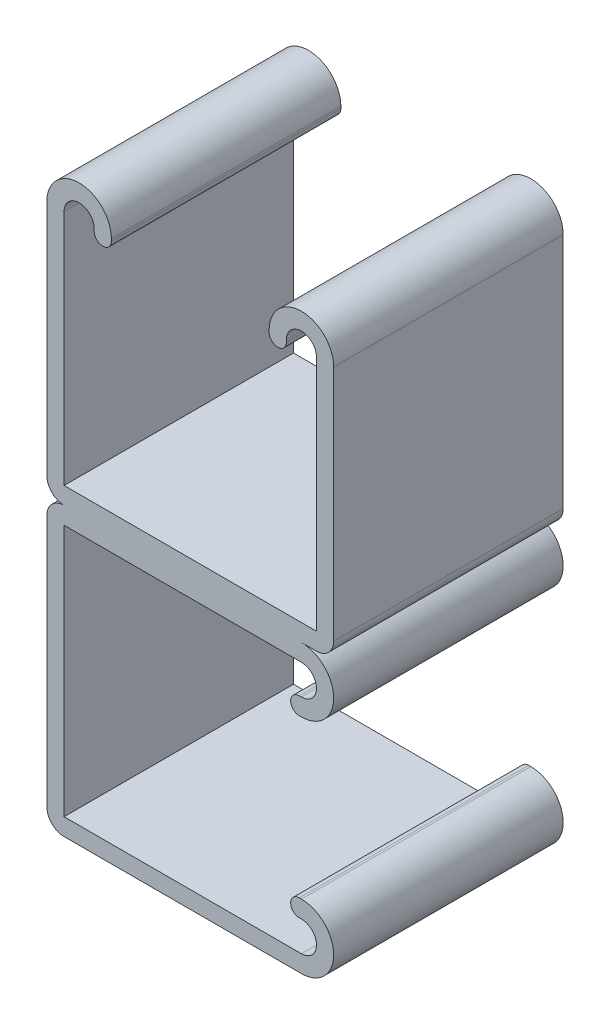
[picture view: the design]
ISO-10303-21;
HEADER;
FILE_DESCRIPTION(('STEP AP214'),'2;1');
FILE_NAME('part.step','',(''),(''),'','','');
FILE_SCHEMA(('AUTOMOTIVE_DESIGN { 1 0 10303 214 1 1 1 1 }'));
ENDSEC;
DATA;
#1=APPLICATION_CONTEXT('core data for automotive mechanical design processes');
#2=APPLICATION_PROTOCOL_DEFINITION('international standard','automotive_design',2000,#1);
#3=PRODUCT_CONTEXT('',#1,'mechanical');
#4=PRODUCT('Part','Part','',(#3));
#5=PRODUCT_RELATED_PRODUCT_CATEGORY('part','',(#4));
#6=PRODUCT_DEFINITION_FORMATION('','',#4);
#7=PRODUCT_DEFINITION_CONTEXT('part definition',#1,'design');
#8=PRODUCT_DEFINITION('design','',#6,#7);
#9=PRODUCT_DEFINITION_SHAPE('','',#8);
#10=(LENGTH_UNIT() NAMED_UNIT(*) SI_UNIT(.MILLI.,.METRE.));
#11=(NAMED_UNIT(*) PLANE_ANGLE_UNIT() SI_UNIT($,.RADIAN.));
#12=(NAMED_UNIT(*) SI_UNIT($,.STERADIAN.) SOLID_ANGLE_UNIT());
#13=UNCERTAINTY_MEASURE_WITH_UNIT(LENGTH_MEASURE(1.E-05),#10,'distance_accuracy_value','');
#14=(GEOMETRIC_REPRESENTATION_CONTEXT(3) GLOBAL_UNCERTAINTY_ASSIGNED_CONTEXT((#13)) GLOBAL_UNIT_ASSIGNED_CONTEXT((#10,
#11,#12)) REPRESENTATION_CONTEXT('',''));
#15=CARTESIAN_POINT('',(0.,0.,0.));
#16=DIRECTION('',(0.,0.,1.));
#17=DIRECTION('',(1.,0.,0.));
#18=AXIS2_PLACEMENT_3D('',#15,#16,#17);
#19=CARTESIAN_POINT('',(1.905,0.,12.7));
#20=DIRECTION('',(0.,1.,0.));
#21=DIRECTION('',(0.,0.,1.));
#22=AXIS2_PLACEMENT_3D('',#19,#20,#21);
#23=PLANE('',#22);
#24=DIRECTION('',(0.,0.,-1.));
#25=VECTOR('',#24,1.);
#26=CARTESIAN_POINT('',(28.178125,2.93849150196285E-13,12.7));
#27=LINE('',#26,#25);
#28=CARTESIAN_POINT('',(28.178125,0.,12.7));
#29=VERTEX_POINT('',#28);
#30=CARTESIAN_POINT('',(28.178125,2.93849150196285E-13,-12.7));
#31=VERTEX_POINT('',#30);
#32=EDGE_CURVE('E205',#29,#31,#27,.T.);
#33=ORIENTED_EDGE('',*,*,#32,.T.);
#34=DIRECTION('',(1.,0.,0.));
#35=VECTOR('',#34,1.);
#36=CARTESIAN_POINT('',(1.905,0.,-12.7));
#37=LINE('',#36,#35);
#38=CARTESIAN_POINT('',(29.845,0.,-12.7));
#39=VERTEX_POINT('',#38);
#40=EDGE_CURVE('E209',#31,#39,#37,.T.);
#41=ORIENTED_EDGE('',*,*,#40,.T.);
#42=DIRECTION('',(0.,0.,-1.));
#43=VECTOR('',#42,1.);
#44=CARTESIAN_POINT('',(29.845,0.,12.7));
#45=LINE('',#44,#43);
#46=CARTESIAN_POINT('',(29.845,0.,12.7));
#47=VERTEX_POINT('',#46);
#48=EDGE_CURVE('E271',#47,#39,#45,.T.);
#49=ORIENTED_EDGE('',*,*,#48,.F.);
#50=DIRECTION('',(1.,0.,0.));
#51=VECTOR('',#50,1.);
#52=CARTESIAN_POINT('',(1.905,0.,12.7));
#53=LINE('',#52,#51);
#54=EDGE_CURVE('E48',#29,#47,#53,.T.);
#55=ORIENTED_EDGE('',*,*,#54,.F.);
#56=EDGE_LOOP('',(#33,#41,#49,#55));
#57=FACE_BOUND('',#56,.T.);
#58=ADVANCED_FACE('F33',(#57),#23,.F.);
#59=CARTESIAN_POINT('',(3.571875,28.178125,12.7));
#60=DIRECTION('',(0.,0.,-1.));
#61=DIRECTION('',(-1.,0.,0.));
#62=AXIS2_PLACEMENT_3D('',#59,#60,#61);
#63=CYLINDRICAL_SURFACE('',#62,3.571875);
#64=CARTESIAN_POINT('',(3.571875,28.178125,-12.7));
#65=DIRECTION('',(0.,0.,1.));
#66=DIRECTION('',(-1.,0.,0.));
#67=AXIS2_PLACEMENT_3D('',#64,#65,#66);
#68=CIRCLE('',#67,3.571875);
#69=CARTESIAN_POINT('',(7.14375,28.178125,-12.7));
#70=VERTEX_POINT('',#69);
#71=CARTESIAN_POINT('',(0.,28.178125,-12.7));
#72=VERTEX_POINT('',#71);
#73=EDGE_CURVE('E201',#70,#72,#68,.T.);
#74=ORIENTED_EDGE('',*,*,#73,.T.);
#75=DIRECTION('',(0.,0.,-1.));
#76=VECTOR('',#75,1.);
#77=CARTESIAN_POINT('',(0.,28.178125,12.7));
#78=LINE('',#77,#76);
#79=CARTESIAN_POINT('',(0.,28.178125,12.7));
#80=VERTEX_POINT('',#79);
#81=EDGE_CURVE('E11',#80,#72,#78,.T.);
#82=ORIENTED_EDGE('',*,*,#81,.F.);
#83=CARTESIAN_POINT('',(3.571875,28.178125,12.7));
#84=DIRECTION('',(0.,0.,1.));
#85=DIRECTION('',(-1.,0.,0.));
#86=AXIS2_PLACEMENT_3D('',#83,#84,#85);
#87=CIRCLE('',#86,3.571875);
#88=CARTESIAN_POINT('',(7.14375,28.178125,12.7));
#89=VERTEX_POINT('',#88);
#90=EDGE_CURVE('E237',#89,#80,#87,.T.);
#91=ORIENTED_EDGE('',*,*,#90,.F.);
#92=DIRECTION('',(0.,0.,-1.));
#93=VECTOR('',#92,1.);
#94=CARTESIAN_POINT('',(7.14375,28.178125,12.7));
#95=LINE('',#94,#93);
#96=EDGE_CURVE('E197',#89,#70,#95,.T.);
#97=ORIENTED_EDGE('',*,*,#96,.T.);
#98=EDGE_LOOP('',(#74,#82,#91,#97));
#99=FACE_BOUND('',#98,.T.);
#100=ADVANCED_FACE('F35',(#99),#63,.T.);
#101=CARTESIAN_POINT('',(0.,28.178125,12.7));
#102=DIRECTION('',(1.,0.,0.));
#103=DIRECTION('',(0.,1.,0.));
#104=AXIS2_PLACEMENT_3D('',#101,#102,#103);
#105=PLANE('',#104);
#106=DIRECTION('',(0.,-1.,0.));
#107=VECTOR('',#106,1.);
#108=CARTESIAN_POINT('',(0.,28.178125,-12.7));
#109=LINE('',#108,#107);
#110=CARTESIAN_POINT('',(0.,1.905,-12.7));
#111=VERTEX_POINT('',#110);
#112=EDGE_CURVE('E204',#72,#111,#109,.T.);
#113=ORIENTED_EDGE('',*,*,#112,.T.);
#114=DIRECTION('',(0.,0.,-1.));
#115=VECTOR('',#114,1.);
#116=CARTESIAN_POINT('',(0.,1.905,12.7));
#117=LINE('',#116,#115);
#118=CARTESIAN_POINT('',(0.,1.905,12.7));
#119=VERTEX_POINT('',#118);
#120=EDGE_CURVE('E41',#119,#111,#117,.T.);
#121=ORIENTED_EDGE('',*,*,#120,.F.);
#122=DIRECTION('',(0.,-1.,0.));
#123=VECTOR('',#122,1.);
#124=CARTESIAN_POINT('',(0.,28.178125,12.7));
#125=LINE('',#124,#123);
#126=EDGE_CURVE('E128',#80,#119,#125,.T.);
#127=ORIENTED_EDGE('',*,*,#126,.F.);
#128=ORIENTED_EDGE('',*,*,#81,.T.);
#129=EDGE_LOOP('',(#113,#121,#127,#128));
#130=FACE_BOUND('',#129,.T.);
#131=ADVANCED_FACE('F636',(#130),#105,.F.);
#132=CARTESIAN_POINT('',(1.905,1.905,12.7));
#133=DIRECTION('',(0.,0.,-1.));
#134=DIRECTION('',(-1.,0.,0.));
#135=AXIS2_PLACEMENT_3D('',#132,#133,#134);
#136=CYLINDRICAL_SURFACE('',#135,1.905);
#137=CARTESIAN_POINT('',(1.905,1.905,-12.7));
#138=DIRECTION('',(0.,0.,1.));
#139=DIRECTION('',(-1.,0.,0.));
#140=AXIS2_PLACEMENT_3D('',#137,#138,#139);
#141=CIRCLE('',#140,1.905);
#142=CARTESIAN_POINT('',(1.905,0.,-12.7));
#143=VERTEX_POINT('',#142);
#144=EDGE_CURVE('E207',#111,#143,#141,.T.);
#145=ORIENTED_EDGE('',*,*,#144,.T.);
#146=DIRECTION('',(0.,0.,-1.));
#147=VECTOR('',#146,1.);
#148=CARTESIAN_POINT('',(1.905,0.,12.7));
#149=LINE('',#148,#147);
#150=CARTESIAN_POINT('',(1.905,0.,12.7));
#151=VERTEX_POINT('',#150);
#152=EDGE_CURVE('E274',#151,#143,#149,.T.);
#153=ORIENTED_EDGE('',*,*,#152,.F.);
#154=CARTESIAN_POINT('',(1.905,1.905,12.7));
#155=DIRECTION('',(0.,0.,1.));
#156=DIRECTION('',(-1.,0.,0.));
#157=AXIS2_PLACEMENT_3D('',#154,#155,#156);
#158=CIRCLE('',#157,1.905);
#159=EDGE_CURVE('E282',#119,#151,#158,.T.);
#160=ORIENTED_EDGE('',*,*,#159,.F.);
#161=ORIENTED_EDGE('',*,*,#120,.T.);
#162=EDGE_LOOP('',(#145,#153,#160,#161));
#163=FACE_BOUND('',#162,.T.);
#164=ADVANCED_FACE('F280',(#163),#136,.T.);
#165=CARTESIAN_POINT('',(29.845,1.905,12.7));
#166=DIRECTION('',(0.,0.,-1.));
#167=DIRECTION('',(-1.,0.,0.));
#168=AXIS2_PLACEMENT_3D('',#165,#166,#167);
#169=CYLINDRICAL_SURFACE('',#168,1.905);
#170=CARTESIAN_POINT('',(29.845,1.905,-12.7));
#171=DIRECTION('',(0.,0.,1.));
#172=DIRECTION('',(1.,0.,0.));
#173=AXIS2_PLACEMENT_3D('',#170,#171,#172);
#174=CIRCLE('',#173,1.905);
#175=CARTESIAN_POINT('',(31.75,1.905,-12.7));
#176=VERTEX_POINT('',#175);
#177=EDGE_CURVE('E211',#39,#176,#174,.T.);
#178=ORIENTED_EDGE('',*,*,#177,.T.);
#179=DIRECTION('',(0.,0.,-1.));
#180=VECTOR('',#179,1.);
#181=CARTESIAN_POINT('',(31.75,1.905,12.7));
#182=LINE('',#181,#180);
#183=CARTESIAN_POINT('',(31.75,1.905,12.7));
#184=VERTEX_POINT('',#183);
#185=EDGE_CURVE('E268',#184,#176,#182,.T.);
#186=ORIENTED_EDGE('',*,*,#185,.F.);
#187=CARTESIAN_POINT('',(29.845,1.905,12.7));
#188=DIRECTION('',(0.,0.,1.));
#189=DIRECTION('',(1.,0.,0.));
#190=AXIS2_PLACEMENT_3D('',#187,#188,#189);
#191=CIRCLE('',#190,1.905);
#192=EDGE_CURVE('E400',#47,#184,#191,.T.);
#193=ORIENTED_EDGE('',*,*,#192,.F.);
#194=ORIENTED_EDGE('',*,*,#48,.T.);
#195=EDGE_LOOP('',(#178,#186,#193,#194));
#196=FACE_BOUND('',#195,.T.);
#197=ADVANCED_FACE('F639',(#196),#169,.T.);
#198=CARTESIAN_POINT('',(31.75,1.905,12.7));
#199=DIRECTION('',(-1.,0.,0.));
#200=DIRECTION('',(0.,-1.,0.));
#201=AXIS2_PLACEMENT_3D('',#198,#199,#200);
#202=PLANE('',#201);
#203=DIRECTION('',(0.,1.,0.));
#204=VECTOR('',#203,1.);
#205=CARTESIAN_POINT('',(31.75,1.905,-12.7));
#206=LINE('',#205,#204);
#207=CARTESIAN_POINT('',(31.75,28.178125,-12.7));
#208=VERTEX_POINT('',#207);
#209=EDGE_CURVE('E213',#176,#208,#206,.T.);
#210=ORIENTED_EDGE('',*,*,#209,.T.);
#211=DIRECTION('',(0.,0.,-1.));
#212=VECTOR('',#211,1.);
#213=CARTESIAN_POINT('',(31.75,28.178125,12.7));
#214=LINE('',#213,#212);
#215=CARTESIAN_POINT('',(31.75,28.178125,12.7));
#216=VERTEX_POINT('',#215);
#217=EDGE_CURVE('E265',#216,#208,#214,.T.);
#218=ORIENTED_EDGE('',*,*,#217,.F.);
#219=DIRECTION('',(0.,1.,0.));
#220=VECTOR('',#219,1.);
#221=CARTESIAN_POINT('',(31.75,1.905,12.7));
#222=LINE('',#221,#220);
#223=EDGE_CURVE('E402',#184,#216,#222,.T.);
#224=ORIENTED_EDGE('',*,*,#223,.F.);
#225=ORIENTED_EDGE('',*,*,#185,.T.);
#226=EDGE_LOOP('',(#210,#218,#224,#225));
#227=FACE_BOUND('',#226,.T.);
#228=ADVANCED_FACE('F658',(#227),#202,.F.);
#229=CARTESIAN_POINT('',(28.178125,28.178125,12.7));
#230=DIRECTION('',(0.,0.,-1.));
#231=DIRECTION('',(-1.,0.,0.));
#232=AXIS2_PLACEMENT_3D('',#229,#230,#231);
#233=CYLINDRICAL_SURFACE('',#232,3.571875);
#234=CARTESIAN_POINT('',(28.178125,28.178125,-12.7));
#235=DIRECTION('',(0.,0.,1.));
#236=DIRECTION('',(1.,0.,0.));
#237=AXIS2_PLACEMENT_3D('',#234,#235,#236);
#238=CIRCLE('',#237,3.571875);
#239=CARTESIAN_POINT('',(24.60625,28.178125,-12.7));
#240=VERTEX_POINT('',#239);
#241=EDGE_CURVE('E215',#208,#240,#238,.T.);
#242=ORIENTED_EDGE('',*,*,#241,.T.);
#243=DIRECTION('',(0.,0.,-1.));
#244=VECTOR('',#243,1.);
#245=CARTESIAN_POINT('',(24.60625,28.178125,12.7));
#246=LINE('',#245,#244);
#247=CARTESIAN_POINT('',(24.60625,28.178125,12.7));
#248=VERTEX_POINT('',#247);
#249=EDGE_CURVE('E262',#248,#240,#246,.T.);
#250=ORIENTED_EDGE('',*,*,#249,.F.);
#251=CARTESIAN_POINT('',(28.178125,28.178125,12.7));
#252=DIRECTION('',(0.,0.,1.));
#253=DIRECTION('',(1.,0.,0.));
#254=AXIS2_PLACEMENT_3D('',#251,#252,#253);
#255=CIRCLE('',#254,3.571875);
#256=EDGE_CURVE('E404',#216,#248,#255,.T.);
#257=ORIENTED_EDGE('',*,*,#256,.F.);
#258=ORIENTED_EDGE('',*,*,#217,.T.);
#259=EDGE_LOOP('',(#242,#250,#257,#258));
#260=FACE_BOUND('',#259,.T.);
#261=ADVANCED_FACE('F665',(#260),#233,.T.);
#262=CARTESIAN_POINT('',(24.60625,28.178125,12.7));
#263=DIRECTION('',(1.,0.,0.));
#264=DIRECTION('',(0.,1.,0.));
#265=AXIS2_PLACEMENT_3D('',#262,#263,#264);
#266=PLANE('',#265);
#267=DIRECTION('',(0.,-1.,0.));
#268=VECTOR('',#267,1.);
#269=CARTESIAN_POINT('',(24.60625,28.178125,-12.7));
#270=LINE('',#269,#268);
#271=CARTESIAN_POINT('',(24.60625,27.94,-12.7));
#272=VERTEX_POINT('',#271);
#273=EDGE_CURVE('E217',#240,#272,#270,.T.);
#274=ORIENTED_EDGE('',*,*,#273,.T.);
#275=DIRECTION('',(0.,0.,-1.));
#276=VECTOR('',#275,1.);
#277=CARTESIAN_POINT('',(24.60625,27.94,12.7));
#278=LINE('',#277,#276);
#279=CARTESIAN_POINT('',(24.60625,27.94,12.7));
#280=VERTEX_POINT('',#279);
#281=EDGE_CURVE('E259',#280,#272,#278,.T.);
#282=ORIENTED_EDGE('',*,*,#281,.F.);
#283=DIRECTION('',(0.,-1.,0.));
#284=VECTOR('',#283,1.);
#285=CARTESIAN_POINT('',(24.60625,28.178125,12.7));
#286=LINE('',#285,#284);
#287=EDGE_CURVE('E406',#248,#280,#286,.T.);
#288=ORIENTED_EDGE('',*,*,#287,.F.);
#289=ORIENTED_EDGE('',*,*,#249,.T.);
#290=EDGE_LOOP('',(#274,#282,#288,#289));
#291=FACE_BOUND('',#290,.T.);
#292=ADVANCED_FACE('F672',(#291),#266,.F.);
#293=CARTESIAN_POINT('',(25.55875,27.94,12.7));
#294=DIRECTION('',(0.,0.,-1.));
#295=DIRECTION('',(-1.,0.,0.));
#296=AXIS2_PLACEMENT_3D('',#293,#294,#295);
#297=CYLINDRICAL_SURFACE('',#296,0.952500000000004);
#298=CARTESIAN_POINT('',(25.55875,27.94,-12.7));
#299=DIRECTION('',(0.,0.,1.));
#300=DIRECTION('',(1.,0.,0.));
#301=AXIS2_PLACEMENT_3D('',#298,#299,#300);
#302=CIRCLE('',#301,0.952500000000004);
#303=CARTESIAN_POINT('',(26.51125,27.94,-12.7));
#304=VERTEX_POINT('',#303);
#305=EDGE_CURVE('E219',#272,#304,#302,.T.);
#306=ORIENTED_EDGE('',*,*,#305,.T.);
#307=DIRECTION('',(0.,0.,-1.));
#308=VECTOR('',#307,1.);
#309=CARTESIAN_POINT('',(26.51125,27.94,12.7));
#310=LINE('',#309,#308);
#311=CARTESIAN_POINT('',(26.51125,27.94,12.7));
#312=VERTEX_POINT('',#311);
#313=EDGE_CURVE('E256',#312,#304,#310,.T.);
#314=ORIENTED_EDGE('',*,*,#313,.F.);
#315=CARTESIAN_POINT('',(25.55875,27.94,12.7));
#316=DIRECTION('',(0.,0.,1.));
#317=DIRECTION('',(1.,0.,0.));
#318=AXIS2_PLACEMENT_3D('',#315,#316,#317);
#319=CIRCLE('',#318,0.952500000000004);
#320=EDGE_CURVE('E408',#280,#312,#319,.T.);
#321=ORIENTED_EDGE('',*,*,#320,.F.);
#322=ORIENTED_EDGE('',*,*,#281,.T.);
#323=EDGE_LOOP('',(#306,#314,#321,#322));
#324=FACE_BOUND('',#323,.T.);
#325=ADVANCED_FACE('F680',(#324),#297,.T.);
#326=CARTESIAN_POINT('',(26.51125,28.178125,12.7));
#327=DIRECTION('',(-1.,0.,0.));
#328=DIRECTION('',(0.,-1.,0.));
#329=AXIS2_PLACEMENT_3D('',#326,#327,#328);
#330=PLANE('',#329);
#331=DIRECTION('',(0.,1.,0.));
#332=VECTOR('',#331,1.);
#333=CARTESIAN_POINT('',(26.51125,28.178125,-12.7));
#334=LINE('',#333,#332);
#335=CARTESIAN_POINT('',(26.51125,28.178125,-12.7));
#336=VERTEX_POINT('',#335);
#337=EDGE_CURVE('E221',#304,#336,#334,.T.);
#338=ORIENTED_EDGE('',*,*,#337,.T.);
#339=DIRECTION('',(0.,0.,-1.));
#340=VECTOR('',#339,1.);
#341=CARTESIAN_POINT('',(26.51125,28.178125,12.7));
#342=LINE('',#341,#340);
#343=CARTESIAN_POINT('',(26.51125,28.178125,12.7));
#344=VERTEX_POINT('',#343);
#345=EDGE_CURVE('E253',#344,#336,#342,.T.);
#346=ORIENTED_EDGE('',*,*,#345,.F.);
#347=DIRECTION('',(0.,1.,0.));
#348=VECTOR('',#347,1.);
#349=CARTESIAN_POINT('',(26.51125,28.178125,12.7));
#350=LINE('',#349,#348);
#351=EDGE_CURVE('E410',#312,#344,#350,.T.);
#352=ORIENTED_EDGE('',*,*,#351,.F.);
#353=ORIENTED_EDGE('',*,*,#313,.T.);
#354=EDGE_LOOP('',(#338,#346,#352,#353));
#355=FACE_BOUND('',#354,.T.);
#356=ADVANCED_FACE('F688',(#355),#330,.F.);
#357=CARTESIAN_POINT('',(28.178125,28.178125,12.7));
#358=DIRECTION('',(0.,0.,-1.));
#359=DIRECTION('',(-1.,0.,0.));
#360=AXIS2_PLACEMENT_3D('',#357,#358,#359);
#361=CYLINDRICAL_SURFACE('',#360,1.66687500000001);
#362=CARTESIAN_POINT('',(28.178125,28.178125,-12.7));
#363=DIRECTION('',(0.,0.,-1.));
#364=DIRECTION('',(1.,0.,0.));
#365=AXIS2_PLACEMENT_3D('',#362,#363,#364);
#366=CIRCLE('',#365,1.66687500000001);
#367=CARTESIAN_POINT('',(29.845,28.178125,-12.7));
#368=VERTEX_POINT('',#367);
#369=EDGE_CURVE('E223',#336,#368,#366,.T.);
#370=ORIENTED_EDGE('',*,*,#369,.T.);
#371=DIRECTION('',(0.,0.,-1.));
#372=VECTOR('',#371,1.);
#373=CARTESIAN_POINT('',(29.845,28.178125,12.7));
#374=LINE('',#373,#372);
#375=CARTESIAN_POINT('',(29.845,28.178125,12.7));
#376=VERTEX_POINT('',#375);
#377=EDGE_CURVE('E250',#376,#368,#374,.T.);
#378=ORIENTED_EDGE('',*,*,#377,.F.);
#379=CARTESIAN_POINT('',(28.178125,28.178125,12.7));
#380=DIRECTION('',(0.,0.,-1.));
#381=DIRECTION('',(1.,0.,0.));
#382=AXIS2_PLACEMENT_3D('',#379,#380,#381);
#383=CIRCLE('',#382,1.66687500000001);
#384=EDGE_CURVE('E412',#344,#376,#383,.T.);
#385=ORIENTED_EDGE('',*,*,#384,.F.);
#386=ORIENTED_EDGE('',*,*,#345,.T.);
#387=EDGE_LOOP('',(#370,#378,#385,#386));
#388=FACE_BOUND('',#387,.T.);
#389=ADVANCED_FACE('F696',(#388),#361,.F.);
#390=CARTESIAN_POINT('',(29.845,1.905,12.7));
#391=DIRECTION('',(1.,0.,0.));
#392=DIRECTION('',(0.,1.,0.));
#393=AXIS2_PLACEMENT_3D('',#390,#391,#392);
#394=PLANE('',#393);
#395=DIRECTION('',(0.,-1.,0.));
#396=VECTOR('',#395,1.);
#397=CARTESIAN_POINT('',(29.845,1.905,-12.7));
#398=LINE('',#397,#396);
#399=CARTESIAN_POINT('',(29.845,1.905,-12.7));
#400=VERTEX_POINT('',#399);
#401=EDGE_CURVE('E225',#368,#400,#398,.T.);
#402=ORIENTED_EDGE('',*,*,#401,.T.);
#403=DIRECTION('',(0.,0.,-1.));
#404=VECTOR('',#403,1.);
#405=CARTESIAN_POINT('',(29.845,1.905,12.7));
#406=LINE('',#405,#404);
#407=CARTESIAN_POINT('',(29.845,1.905,12.7));
#408=VERTEX_POINT('',#407);
#409=EDGE_CURVE('E247',#408,#400,#406,.T.);
#410=ORIENTED_EDGE('',*,*,#409,.F.);
#411=DIRECTION('',(0.,-1.,0.));
#412=VECTOR('',#411,1.);
#413=CARTESIAN_POINT('',(29.845,1.905,12.7));
#414=LINE('',#413,#412);
#415=EDGE_CURVE('E414',#376,#408,#414,.T.);
#416=ORIENTED_EDGE('',*,*,#415,.F.);
#417=ORIENTED_EDGE('',*,*,#377,.T.);
#418=EDGE_LOOP('',(#402,#410,#416,#417));
#419=FACE_BOUND('',#418,.T.);
#420=ADVANCED_FACE('F704',(#419),#394,.F.);
#421=CARTESIAN_POINT('',(1.905,1.905,12.7));
#422=DIRECTION('',(0.,-1.,0.));
#423=DIRECTION('',(0.,0.,-1.));
#424=AXIS2_PLACEMENT_3D('',#421,#422,#423);
#425=PLANE('',#424);
#426=DIRECTION('',(-1.,0.,0.));
#427=VECTOR('',#426,1.);
#428=CARTESIAN_POINT('',(1.905,1.905,-12.7));
#429=LINE('',#428,#427);
#430=CARTESIAN_POINT('',(1.905,1.905,-12.7));
#431=VERTEX_POINT('',#430);
#432=EDGE_CURVE('E227',#400,#431,#429,.T.);
#433=ORIENTED_EDGE('',*,*,#432,.T.);
#434=DIRECTION('',(0.,0.,-1.));
#435=VECTOR('',#434,1.);
#436=CARTESIAN_POINT('',(1.905,1.905,12.7));
#437=LINE('',#436,#435);
#438=CARTESIAN_POINT('',(1.905,1.905,12.7));
#439=VERTEX_POINT('',#438);
#440=EDGE_CURVE('E244',#439,#431,#437,.T.);
#441=ORIENTED_EDGE('',*,*,#440,.F.);
#442=DIRECTION('',(-1.,0.,0.));
#443=VECTOR('',#442,1.);
#444=CARTESIAN_POINT('',(1.905,1.905,12.7));
#445=LINE('',#444,#443);
#446=EDGE_CURVE('E416',#408,#439,#445,.T.);
#447=ORIENTED_EDGE('',*,*,#446,.F.);
#448=ORIENTED_EDGE('',*,*,#409,.T.);
#449=EDGE_LOOP('',(#433,#441,#447,#448));
#450=FACE_BOUND('',#449,.T.);
#451=ADVANCED_FACE('F712',(#450),#425,.F.);
#452=CARTESIAN_POINT('',(1.905,28.178125,12.7));
#453=DIRECTION('',(-1.,0.,0.));
#454=DIRECTION('',(0.,-1.,0.));
#455=AXIS2_PLACEMENT_3D('',#452,#453,#454);
#456=PLANE('',#455);
#457=DIRECTION('',(0.,1.,0.));
#458=VECTOR('',#457,1.);
#459=CARTESIAN_POINT('',(1.905,28.178125,-12.7));
#460=LINE('',#459,#458);
#461=CARTESIAN_POINT('',(1.905,28.178125,-12.7));
#462=VERTEX_POINT('',#461);
#463=EDGE_CURVE('E229',#431,#462,#460,.T.);
#464=ORIENTED_EDGE('',*,*,#463,.T.);
#465=DIRECTION('',(0.,0.,-1.));
#466=VECTOR('',#465,1.);
#467=CARTESIAN_POINT('',(1.905,28.178125,12.7));
#468=LINE('',#467,#466);
#469=CARTESIAN_POINT('',(1.905,28.178125,12.7));
#470=VERTEX_POINT('',#469);
#471=EDGE_CURVE('E241',#470,#462,#468,.T.);
#472=ORIENTED_EDGE('',*,*,#471,.F.);
#473=DIRECTION('',(0.,1.,0.));
#474=VECTOR('',#473,1.);
#475=CARTESIAN_POINT('',(1.905,28.178125,12.7));
#476=LINE('',#475,#474);
#477=EDGE_CURVE('E418',#439,#470,#476,.T.);
#478=ORIENTED_EDGE('',*,*,#477,.F.);
#479=ORIENTED_EDGE('',*,*,#440,.T.);
#480=EDGE_LOOP('',(#464,#472,#478,#479));
#481=FACE_BOUND('',#480,.T.);
#482=ADVANCED_FACE('F424',(#481),#456,.F.);
#483=CARTESIAN_POINT('',(3.571875,28.178125,12.7));
#484=DIRECTION('',(0.,0.,-1.));
#485=DIRECTION('',(-1.,0.,0.));
#486=AXIS2_PLACEMENT_3D('',#483,#484,#485);
#487=CYLINDRICAL_SURFACE('',#486,1.666875);
#488=CARTESIAN_POINT('',(3.571875,28.178125,-12.7));
#489=DIRECTION('',(0.,0.,-1.));
#490=DIRECTION('',(-1.,0.,0.));
#491=AXIS2_PLACEMENT_3D('',#488,#489,#490);
#492=CIRCLE('',#491,1.666875);
#493=CARTESIAN_POINT('',(5.23875,28.178125,-12.7));
#494=VERTEX_POINT('',#493);
#495=EDGE_CURVE('E231',#462,#494,#492,.T.);
#496=ORIENTED_EDGE('',*,*,#495,.T.);
#497=DIRECTION('',(0.,0.,-1.));
#498=VECTOR('',#497,1.);
#499=CARTESIAN_POINT('',(5.23875,28.178125,12.7));
#500=LINE('',#499,#498);
#501=CARTESIAN_POINT('',(5.23875,28.178125,12.7));
#502=VERTEX_POINT('',#501);
#503=EDGE_CURVE('E192',#502,#494,#500,.T.);
#504=ORIENTED_EDGE('',*,*,#503,.F.);
#505=CARTESIAN_POINT('',(3.571875,28.178125,12.7));
#506=DIRECTION('',(0.,0.,-1.));
#507=DIRECTION('',(-1.,0.,0.));
#508=AXIS2_PLACEMENT_3D('',#505,#506,#507);
#509=CIRCLE('',#508,1.666875);
#510=EDGE_CURVE('E180',#470,#502,#509,.T.);
#511=ORIENTED_EDGE('',*,*,#510,.F.);
#512=ORIENTED_EDGE('',*,*,#471,.T.);
#513=EDGE_LOOP('',(#496,#504,#511,#512));
#514=FACE_BOUND('',#513,.T.);
#515=ADVANCED_FACE('F428',(#514),#487,.F.);
#516=CARTESIAN_POINT('',(5.23875,28.178125,12.7));
#517=DIRECTION('',(1.,0.,0.));
#518=DIRECTION('',(0.,1.,0.));
#519=AXIS2_PLACEMENT_3D('',#516,#517,#518);
#520=PLANE('',#519);
#521=DIRECTION('',(0.,-1.,0.));
#522=VECTOR('',#521,1.);
#523=CARTESIAN_POINT('',(5.23875,28.178125,-12.7));
#524=LINE('',#523,#522);
#525=CARTESIAN_POINT('',(5.23875,27.94,-12.7));
#526=VERTEX_POINT('',#525);
#527=EDGE_CURVE('E189',#494,#526,#524,.T.);
#528=ORIENTED_EDGE('',*,*,#527,.T.);
#529=DIRECTION('',(0.,0.,-1.));
#530=VECTOR('',#529,1.);
#531=CARTESIAN_POINT('',(5.23875,27.94,12.7));
#532=LINE('',#531,#530);
#533=CARTESIAN_POINT('',(5.23875,27.94,12.7));
#534=VERTEX_POINT('',#533);
#535=EDGE_CURVE('E186',#534,#526,#532,.T.);
#536=ORIENTED_EDGE('',*,*,#535,.F.);
#537=DIRECTION('',(0.,-1.,0.));
#538=VECTOR('',#537,1.);
#539=CARTESIAN_POINT('',(5.23875,28.178125,12.7));
#540=LINE('',#539,#538);
#541=EDGE_CURVE('E173',#502,#534,#540,.T.);
#542=ORIENTED_EDGE('',*,*,#541,.F.);
#543=ORIENTED_EDGE('',*,*,#503,.T.);
#544=EDGE_LOOP('',(#528,#536,#542,#543));
#545=FACE_BOUND('',#544,.T.);
#546=ADVANCED_FACE('F187',(#545),#520,.F.);
#547=CARTESIAN_POINT('',(6.19125,27.94,12.7));
#548=DIRECTION('',(0.,0.,-1.));
#549=DIRECTION('',(-1.,0.,0.));
#550=AXIS2_PLACEMENT_3D('',#547,#548,#549);
#551=CYLINDRICAL_SURFACE('',#550,0.9525);
#552=CARTESIAN_POINT('',(6.19125,27.94,-12.7));
#553=DIRECTION('',(0.,0.,1.));
#554=DIRECTION('',(-1.,0.,0.));
#555=AXIS2_PLACEMENT_3D('',#552,#553,#554);
#556=CIRCLE('',#555,0.9525);
#557=CARTESIAN_POINT('',(7.14375,27.94,-12.7));
#558=VERTEX_POINT('',#557);
#559=EDGE_CURVE('E234',#526,#558,#556,.T.);
#560=ORIENTED_EDGE('',*,*,#559,.T.);
#561=DIRECTION('',(0.,0.,-1.));
#562=VECTOR('',#561,1.);
#563=CARTESIAN_POINT('',(7.14375,27.94,12.7));
#564=LINE('',#563,#562);
#565=CARTESIAN_POINT('',(7.14375,27.94,12.7));
#566=VERTEX_POINT('',#565);
#567=EDGE_CURVE('E193',#566,#558,#564,.T.);
#568=ORIENTED_EDGE('',*,*,#567,.F.);
#569=CARTESIAN_POINT('',(6.19125,27.94,12.7));
#570=DIRECTION('',(0.,0.,1.));
#571=DIRECTION('',(-1.,0.,0.));
#572=AXIS2_PLACEMENT_3D('',#569,#570,#571);
#573=CIRCLE('',#572,0.9525);
#574=EDGE_CURVE('E177',#534,#566,#573,.T.);
#575=ORIENTED_EDGE('',*,*,#574,.F.);
#576=ORIENTED_EDGE('',*,*,#535,.T.);
#577=EDGE_LOOP('',(#560,#568,#575,#576));
#578=FACE_BOUND('',#577,.T.);
#579=ADVANCED_FACE('F195',(#578),#551,.T.);
#580=CARTESIAN_POINT('',(7.14375,28.178125,12.7));
#581=DIRECTION('',(-1.,0.,0.));
#582=DIRECTION('',(0.,-1.,0.));
#583=AXIS2_PLACEMENT_3D('',#580,#581,#582);
#584=PLANE('',#583);
#585=DIRECTION('',(0.,1.,0.));
#586=VECTOR('',#585,1.);
#587=CARTESIAN_POINT('',(7.14375,28.178125,-12.7));
#588=LINE('',#587,#586);
#589=EDGE_CURVE('E120',#558,#70,#588,.T.);
#590=ORIENTED_EDGE('',*,*,#589,.T.);
#591=ORIENTED_EDGE('',*,*,#96,.F.);
#592=DIRECTION('',(0.,1.,0.));
#593=VECTOR('',#592,1.);
#594=CARTESIAN_POINT('',(7.14375,28.178125,12.7));
#595=LINE('',#594,#593);
#596=EDGE_CURVE('E57',#566,#89,#595,.T.);
#597=ORIENTED_EDGE('',*,*,#596,.F.);
#598=ORIENTED_EDGE('',*,*,#567,.T.);
#599=EDGE_LOOP('',(#590,#591,#597,#598));
#600=FACE_BOUND('',#599,.T.);
#601=ADVANCED_FACE('F429',(#600),#584,.F.);
#602=CARTESIAN_POINT('',(3.571875,28.178125,12.7));
#603=DIRECTION('',(0.,0.,-1.));
#604=DIRECTION('',(-1.,0.,0.));
#605=AXIS2_PLACEMENT_3D('',#602,#603,#604);
#606=PLANE('',#605);
#607=ORIENTED_EDGE('',*,*,#90,.T.);
#608=ORIENTED_EDGE('',*,*,#126,.T.);
#609=ORIENTED_EDGE('',*,*,#159,.T.);
#610=CARTESIAN_POINT('',(1.90500000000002,-1.90499999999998,12.7));
#611=DIRECTION('',(0.,0.,1.));
#612=DIRECTION('',(0.,1.,0.));
#613=AXIS2_PLACEMENT_3D('',#610,#611,#612);
#614=CIRCLE('',#613,1.905);
#615=CARTESIAN_POINT('',(0.,-1.905,12.7));
#616=VERTEX_POINT('',#615);
#617=EDGE_CURVE('E437',#151,#616,#614,.T.);
#618=ORIENTED_EDGE('',*,*,#617,.T.);
#619=DIRECTION('',(0.,-1.,0.));
#620=VECTOR('',#619,1.);
#621=CARTESIAN_POINT('',(0.,-1.905,12.7));
#622=LINE('',#621,#620);
#623=CARTESIAN_POINT('',(3.1260978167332E-13,-29.845,12.7));
#624=VERTEX_POINT('',#623);
#625=EDGE_CURVE('E440',#616,#624,#622,.T.);
#626=ORIENTED_EDGE('',*,*,#625,.T.);
#627=CARTESIAN_POINT('',(1.90500000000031,-29.845,12.7));
#628=DIRECTION('',(0.,0.,1.));
#629=DIRECTION('',(0.,-1.,0.));
#630=AXIS2_PLACEMENT_3D('',#627,#628,#629);
#631=CIRCLE('',#630,1.905);
#632=CARTESIAN_POINT('',(1.90500000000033,-31.75,12.7));
#633=VERTEX_POINT('',#632);
#634=EDGE_CURVE('E442',#624,#633,#631,.T.);
#635=ORIENTED_EDGE('',*,*,#634,.T.);
#636=DIRECTION('',(1.,0.,0.));
#637=VECTOR('',#636,1.);
#638=CARTESIAN_POINT('',(1.90500000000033,-31.75,12.7));
#639=LINE('',#638,#637);
#640=CARTESIAN_POINT('',(28.1781250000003,-31.7499999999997,12.7));
#641=VERTEX_POINT('',#640);
#642=EDGE_CURVE('E448',#633,#641,#639,.T.);
#643=ORIENTED_EDGE('',*,*,#642,.T.);
#644=CARTESIAN_POINT('',(28.1781250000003,-28.1781249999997,12.7));
#645=DIRECTION('',(0.,0.,1.));
#646=DIRECTION('',(0.,-1.,0.));
#647=AXIS2_PLACEMENT_3D('',#644,#645,#646);
#648=CIRCLE('',#647,3.571875);
#649=CARTESIAN_POINT('',(28.1781250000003,-24.6062499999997,12.7));
#650=VERTEX_POINT('',#649);
#651=EDGE_CURVE('E451',#641,#650,#648,.T.);
#652=ORIENTED_EDGE('',*,*,#651,.T.);
#653=DIRECTION('',(-1.,0.,0.));
#654=VECTOR('',#653,1.);
#655=CARTESIAN_POINT('',(28.1781250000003,-24.6062499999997,12.7));
#656=LINE('',#655,#654);
#657=CARTESIAN_POINT('',(27.9400000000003,-24.6062499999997,12.7));
#658=VERTEX_POINT('',#657);
#659=EDGE_CURVE('E454',#650,#658,#656,.T.);
#660=ORIENTED_EDGE('',*,*,#659,.T.);
#661=CARTESIAN_POINT('',(27.9400000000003,-25.5587499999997,12.7));
#662=DIRECTION('',(0.,0.,1.));
#663=DIRECTION('',(0.,-1.,0.));
#664=AXIS2_PLACEMENT_3D('',#661,#662,#663);
#665=CIRCLE('',#664,0.952500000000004);
#666=CARTESIAN_POINT('',(27.9400000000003,-26.5112499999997,12.7));
#667=VERTEX_POINT('',#666);
#668=EDGE_CURVE('E457',#658,#667,#665,.T.);
#669=ORIENTED_EDGE('',*,*,#668,.T.);
#670=DIRECTION('',(1.,0.,0.));
#671=VECTOR('',#670,1.);
#672=CARTESIAN_POINT('',(28.1781250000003,-26.5112499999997,12.7));
#673=LINE('',#672,#671);
#674=CARTESIAN_POINT('',(28.1781250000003,-26.5112499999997,12.7));
#675=VERTEX_POINT('',#674);
#676=EDGE_CURVE('E460',#667,#675,#673,.T.);
#677=ORIENTED_EDGE('',*,*,#676,.T.);
#678=CARTESIAN_POINT('',(28.1781250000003,-28.1781249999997,12.7));
#679=DIRECTION('',(0.,0.,-1.));
#680=DIRECTION('',(0.,-1.,0.));
#681=AXIS2_PLACEMENT_3D('',#678,#679,#680);
#682=CIRCLE('',#681,1.66687500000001);
#683=CARTESIAN_POINT('',(28.1781250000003,-29.8449999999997,12.7));
#684=VERTEX_POINT('',#683);
#685=EDGE_CURVE('E463',#675,#684,#682,.T.);
#686=ORIENTED_EDGE('',*,*,#685,.T.);
#687=DIRECTION('',(-1.,0.,0.));
#688=VECTOR('',#687,1.);
#689=CARTESIAN_POINT('',(1.90500000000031,-29.845,12.7));
#690=LINE('',#689,#688);
#691=CARTESIAN_POINT('',(1.90500000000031,-29.845,12.7));
#692=VERTEX_POINT('',#691);
#693=EDGE_CURVE('E466',#684,#692,#690,.T.);
#694=ORIENTED_EDGE('',*,*,#693,.T.);
#695=DIRECTION('',(0.,1.,0.));
#696=VECTOR('',#695,1.);
#697=CARTESIAN_POINT('',(1.90500000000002,-1.90499999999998,12.7));
#698=LINE('',#697,#696);
#699=CARTESIAN_POINT('',(1.90500000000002,-1.90499999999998,12.7));
#700=VERTEX_POINT('',#699);
#701=EDGE_CURVE('E469',#692,#700,#698,.T.);
#702=ORIENTED_EDGE('',*,*,#701,.T.);
#703=DIRECTION('',(1.,0.,0.));
#704=VECTOR('',#703,1.);
#705=CARTESIAN_POINT('',(28.178125,-1.90499999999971,12.7));
#706=LINE('',#705,#704);
#707=CARTESIAN_POINT('',(28.178125,-1.90499999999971,12.7));
#708=VERTEX_POINT('',#707);
#709=EDGE_CURVE('E472',#700,#708,#706,.T.);
#710=ORIENTED_EDGE('',*,*,#709,.T.);
#711=CARTESIAN_POINT('',(28.178125,-3.57187499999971,12.7));
#712=DIRECTION('',(0.,0.,-1.));
#713=DIRECTION('',(0.,1.,0.));
#714=AXIS2_PLACEMENT_3D('',#711,#712,#713);
#715=CIRCLE('',#714,1.666875);
#716=CARTESIAN_POINT('',(28.1781250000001,-5.23874999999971,12.7));
#717=VERTEX_POINT('',#716);
#718=EDGE_CURVE('E475',#708,#717,#715,.T.);
#719=ORIENTED_EDGE('',*,*,#718,.T.);
#720=DIRECTION('',(-1.,0.,0.));
#721=VECTOR('',#720,1.);
#722=CARTESIAN_POINT('',(28.1781250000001,-5.23874999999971,12.7));
#723=LINE('',#722,#721);
#724=CARTESIAN_POINT('',(27.9400000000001,-5.23874999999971,12.7));
#725=VERTEX_POINT('',#724);
#726=EDGE_CURVE('E478',#717,#725,#723,.T.);
#727=ORIENTED_EDGE('',*,*,#726,.T.);
#728=CARTESIAN_POINT('',(27.9400000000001,-6.19124999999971,12.7));
#729=DIRECTION('',(0.,0.,1.));
#730=DIRECTION('',(0.,1.,0.));
#731=AXIS2_PLACEMENT_3D('',#728,#729,#730);
#732=CIRCLE('',#731,0.9525);
#733=CARTESIAN_POINT('',(27.9400000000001,-7.14374999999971,12.7));
#734=VERTEX_POINT('',#733);
#735=EDGE_CURVE('E481',#725,#734,#732,.T.);
#736=ORIENTED_EDGE('',*,*,#735,.T.);
#737=DIRECTION('',(1.,0.,0.));
#738=VECTOR('',#737,1.);
#739=CARTESIAN_POINT('',(28.1781250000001,-7.14374999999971,12.7));
#740=LINE('',#739,#738);
#741=CARTESIAN_POINT('',(28.1781250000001,-7.14374999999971,12.7));
#742=VERTEX_POINT('',#741);
#743=EDGE_CURVE('E351',#734,#742,#740,.T.);
#744=ORIENTED_EDGE('',*,*,#743,.T.);
#745=CARTESIAN_POINT('',(28.178125,-3.57187499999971,12.7));
#746=DIRECTION('',(0.,0.,1.));
#747=DIRECTION('',(0.,1.,0.));
#748=AXIS2_PLACEMENT_3D('',#745,#746,#747);
#749=CIRCLE('',#748,3.571875);
#750=EDGE_CURVE('E346',#742,#29,#749,.T.);
#751=ORIENTED_EDGE('',*,*,#750,.T.);
#752=ORIENTED_EDGE('',*,*,#54,.T.);
#753=ORIENTED_EDGE('',*,*,#192,.T.);
#754=ORIENTED_EDGE('',*,*,#223,.T.);
#755=ORIENTED_EDGE('',*,*,#256,.T.);
#756=ORIENTED_EDGE('',*,*,#287,.T.);
#757=ORIENTED_EDGE('',*,*,#320,.T.);
#758=ORIENTED_EDGE('',*,*,#351,.T.);
#759=ORIENTED_EDGE('',*,*,#384,.T.);
#760=ORIENTED_EDGE('',*,*,#415,.T.);
#761=ORIENTED_EDGE('',*,*,#446,.T.);
#762=ORIENTED_EDGE('',*,*,#477,.T.);
#763=ORIENTED_EDGE('',*,*,#510,.T.);
#764=ORIENTED_EDGE('',*,*,#541,.T.);
#765=ORIENTED_EDGE('',*,*,#574,.T.);
#766=ORIENTED_EDGE('',*,*,#596,.T.);
#767=EDGE_LOOP('',(#607,#608,#609,#618,#626,#635,#643,#652,#660,#669,#677,#686,#694,#702,#710,
#719,#727,#736,#744,#751,#752,#753,#754,#755,#756,#757,#758,#759,#760,#761,#762,#763,#764,#765,#766));
#768=FACE_BOUND('',#767,.T.);
#769=ADVANCED_FACE('F175',(#768),#606,.F.);
#770=CARTESIAN_POINT('',(3.571875,28.178125,-12.7));
#771=DIRECTION('',(0.,0.,-1.));
#772=DIRECTION('',(-1.,0.,0.));
#773=AXIS2_PLACEMENT_3D('',#770,#771,#772);
#774=PLANE('',#773);
#775=ORIENTED_EDGE('',*,*,#73,.F.);
#776=ORIENTED_EDGE('',*,*,#589,.F.);
#777=ORIENTED_EDGE('',*,*,#559,.F.);
#778=ORIENTED_EDGE('',*,*,#527,.F.);
#779=ORIENTED_EDGE('',*,*,#495,.F.);
#780=ORIENTED_EDGE('',*,*,#463,.F.);
#781=ORIENTED_EDGE('',*,*,#432,.F.);
#782=ORIENTED_EDGE('',*,*,#401,.F.);
#783=ORIENTED_EDGE('',*,*,#369,.F.);
#784=ORIENTED_EDGE('',*,*,#337,.F.);
#785=ORIENTED_EDGE('',*,*,#305,.F.);
#786=ORIENTED_EDGE('',*,*,#273,.F.);
#787=ORIENTED_EDGE('',*,*,#241,.F.);
#788=ORIENTED_EDGE('',*,*,#209,.F.);
#789=ORIENTED_EDGE('',*,*,#177,.F.);
#790=ORIENTED_EDGE('',*,*,#40,.F.);
#791=CARTESIAN_POINT('',(28.178125,-3.57187499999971,-12.7));
#792=DIRECTION('',(0.,0.,1.));
#793=DIRECTION('',(0.,1.,0.));
#794=AXIS2_PLACEMENT_3D('',#791,#792,#793);
#795=CIRCLE('',#794,3.571875);
#796=CARTESIAN_POINT('',(28.1781250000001,-7.14374999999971,-12.7));
#797=VERTEX_POINT('',#796);
#798=EDGE_CURVE('E297',#797,#31,#795,.T.);
#799=ORIENTED_EDGE('',*,*,#798,.F.);
#800=DIRECTION('',(1.,0.,0.));
#801=VECTOR('',#800,1.);
#802=CARTESIAN_POINT('',(28.1781250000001,-7.14374999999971,-12.7));
#803=LINE('',#802,#801);
#804=CARTESIAN_POINT('',(27.9400000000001,-7.14374999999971,-12.7));
#805=VERTEX_POINT('',#804);
#806=EDGE_CURVE('E343',#805,#797,#803,.T.);
#807=ORIENTED_EDGE('',*,*,#806,.F.);
#808=CARTESIAN_POINT('',(27.9400000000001,-6.19124999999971,-12.7));
#809=DIRECTION('',(0.,0.,1.));
#810=DIRECTION('',(0.,1.,0.));
#811=AXIS2_PLACEMENT_3D('',#808,#809,#810);
#812=CIRCLE('',#811,0.9525);
#813=CARTESIAN_POINT('',(27.9400000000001,-5.23874999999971,-12.7));
#814=VERTEX_POINT('',#813);
#815=EDGE_CURVE('E340',#814,#805,#812,.T.);
#816=ORIENTED_EDGE('',*,*,#815,.F.);
#817=DIRECTION('',(-1.,0.,0.));
#818=VECTOR('',#817,1.);
#819=CARTESIAN_POINT('',(28.1781250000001,-5.23874999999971,-12.7));
#820=LINE('',#819,#818);
#821=CARTESIAN_POINT('',(28.1781250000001,-5.23874999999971,-12.7));
#822=VERTEX_POINT('',#821);
#823=EDGE_CURVE('E337',#822,#814,#820,.T.);
#824=ORIENTED_EDGE('',*,*,#823,.F.);
#825=CARTESIAN_POINT('',(28.178125,-3.57187499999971,-12.7));
#826=DIRECTION('',(0.,0.,-1.));
#827=DIRECTION('',(0.,1.,0.));
#828=AXIS2_PLACEMENT_3D('',#825,#826,#827);
#829=CIRCLE('',#828,1.666875);
#830=CARTESIAN_POINT('',(28.178125,-1.90499999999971,-12.7));
#831=VERTEX_POINT('',#830);
#832=EDGE_CURVE('E334',#831,#822,#829,.T.);
#833=ORIENTED_EDGE('',*,*,#832,.F.);
#834=DIRECTION('',(1.,0.,0.));
#835=VECTOR('',#834,1.);
#836=CARTESIAN_POINT('',(28.178125,-1.90499999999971,-12.7));
#837=LINE('',#836,#835);
#838=CARTESIAN_POINT('',(1.90500000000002,-1.90499999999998,-12.7));
#839=VERTEX_POINT('',#838);
#840=EDGE_CURVE('E331',#839,#831,#837,.T.);
#841=ORIENTED_EDGE('',*,*,#840,.F.);
#842=DIRECTION('',(0.,1.,0.));
#843=VECTOR('',#842,1.);
#844=CARTESIAN_POINT('',(1.90500000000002,-1.90499999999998,-12.7));
#845=LINE('',#844,#843);
#846=CARTESIAN_POINT('',(1.90500000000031,-29.845,-12.7));
#847=VERTEX_POINT('',#846);
#848=EDGE_CURVE('E328',#847,#839,#845,.T.);
#849=ORIENTED_EDGE('',*,*,#848,.F.);
#850=DIRECTION('',(-1.,0.,0.));
#851=VECTOR('',#850,1.);
#852=CARTESIAN_POINT('',(1.90500000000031,-29.845,-12.7));
#853=LINE('',#852,#851);
#854=CARTESIAN_POINT('',(28.1781250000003,-29.8449999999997,-12.7));
#855=VERTEX_POINT('',#854);
#856=EDGE_CURVE('E325',#855,#847,#853,.T.);
#857=ORIENTED_EDGE('',*,*,#856,.F.);
#858=CARTESIAN_POINT('',(28.1781250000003,-28.1781249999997,-12.7));
#859=DIRECTION('',(0.,0.,-1.));
#860=DIRECTION('',(0.,-1.,0.));
#861=AXIS2_PLACEMENT_3D('',#858,#859,#860);
#862=CIRCLE('',#861,1.66687500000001);
#863=CARTESIAN_POINT('',(28.1781250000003,-26.5112499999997,-12.7));
#864=VERTEX_POINT('',#863);
#865=EDGE_CURVE('E322',#864,#855,#862,.T.);
#866=ORIENTED_EDGE('',*,*,#865,.F.);
#867=DIRECTION('',(1.,0.,0.));
#868=VECTOR('',#867,1.);
#869=CARTESIAN_POINT('',(28.1781250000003,-26.5112499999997,-12.7));
#870=LINE('',#869,#868);
#871=CARTESIAN_POINT('',(27.9400000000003,-26.5112499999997,-12.7));
#872=VERTEX_POINT('',#871);
#873=EDGE_CURVE('E319',#872,#864,#870,.T.);
#874=ORIENTED_EDGE('',*,*,#873,.F.);
#875=CARTESIAN_POINT('',(27.9400000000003,-25.5587499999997,-12.7));
#876=DIRECTION('',(0.,0.,1.));
#877=DIRECTION('',(0.,-1.,0.));
#878=AXIS2_PLACEMENT_3D('',#875,#876,#877);
#879=CIRCLE('',#878,0.952500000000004);
#880=CARTESIAN_POINT('',(27.9400000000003,-24.6062499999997,-12.7));
#881=VERTEX_POINT('',#880);
#882=EDGE_CURVE('E316',#881,#872,#879,.T.);
#883=ORIENTED_EDGE('',*,*,#882,.F.);
#884=DIRECTION('',(-1.,0.,0.));
#885=VECTOR('',#884,1.);
#886=CARTESIAN_POINT('',(28.1781250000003,-24.6062499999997,-12.7));
#887=LINE('',#886,#885);
#888=CARTESIAN_POINT('',(28.1781250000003,-24.6062499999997,-12.7));
#889=VERTEX_POINT('',#888);
#890=EDGE_CURVE('E313',#889,#881,#887,.T.);
#891=ORIENTED_EDGE('',*,*,#890,.F.);
#892=CARTESIAN_POINT('',(28.1781250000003,-28.1781249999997,-12.7));
#893=DIRECTION('',(0.,0.,1.));
#894=DIRECTION('',(0.,-1.,0.));
#895=AXIS2_PLACEMENT_3D('',#892,#893,#894);
#896=CIRCLE('',#895,3.571875);
#897=CARTESIAN_POINT('',(28.1781250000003,-31.7499999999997,-12.7));
#898=VERTEX_POINT('',#897);
#899=EDGE_CURVE('E310',#898,#889,#896,.T.);
#900=ORIENTED_EDGE('',*,*,#899,.F.);
#901=DIRECTION('',(1.,0.,0.));
#902=VECTOR('',#901,1.);
#903=CARTESIAN_POINT('',(1.90500000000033,-31.75,-12.7));
#904=LINE('',#903,#902);
#905=CARTESIAN_POINT('',(1.90500000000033,-31.75,-12.7));
#906=VERTEX_POINT('',#905);
#907=EDGE_CURVE('E307',#906,#898,#904,.T.);
#908=ORIENTED_EDGE('',*,*,#907,.F.);
#909=CARTESIAN_POINT('',(1.90500000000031,-29.845,-12.7));
#910=DIRECTION('',(0.,0.,1.));
#911=DIRECTION('',(0.,-1.,0.));
#912=AXIS2_PLACEMENT_3D('',#909,#910,#911);
#913=CIRCLE('',#912,1.905);
#914=CARTESIAN_POINT('',(3.1260978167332E-13,-29.845,-12.7));
#915=VERTEX_POINT('',#914);
#916=EDGE_CURVE('E299',#915,#906,#913,.T.);
#917=ORIENTED_EDGE('',*,*,#916,.F.);
#918=DIRECTION('',(0.,-1.,0.));
#919=VECTOR('',#918,1.);
#920=CARTESIAN_POINT('',(0.,-1.905,-12.7));
#921=LINE('',#920,#919);
#922=CARTESIAN_POINT('',(0.,-1.905,-12.7));
#923=VERTEX_POINT('',#922);
#924=EDGE_CURVE('E293',#923,#915,#921,.T.);
#925=ORIENTED_EDGE('',*,*,#924,.F.);
#926=CARTESIAN_POINT('',(1.90500000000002,-1.90499999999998,-12.7));
#927=DIRECTION('',(0.,0.,1.));
#928=DIRECTION('',(0.,1.,0.));
#929=AXIS2_PLACEMENT_3D('',#926,#927,#928);
#930=CIRCLE('',#929,1.905);
#931=EDGE_CURVE('E289',#143,#923,#930,.T.);
#932=ORIENTED_EDGE('',*,*,#931,.F.);
#933=ORIENTED_EDGE('',*,*,#144,.F.);
#934=ORIENTED_EDGE('',*,*,#112,.F.);
#935=EDGE_LOOP('',(#775,#776,#777,#778,#779,#780,#781,#782,#783,#784,#785,#786,#787,#788,#789,
#790,#799,#807,#816,#824,#833,#841,#849,#857,#866,#874,#883,#891,#900,#908,#917,#925,#932,#933,#934));
#936=FACE_BOUND('',#935,.T.);
#937=ADVANCED_FACE('F286',(#936),#774,.T.);
#938=CARTESIAN_POINT('',(28.178125,-3.57187499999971,12.7));
#939=DIRECTION('',(0.,0.,-1.));
#940=DIRECTION('',(-1.,0.,0.));
#941=AXIS2_PLACEMENT_3D('',#938,#939,#940);
#942=CYLINDRICAL_SURFACE('',#941,3.571875);
#943=ORIENTED_EDGE('',*,*,#798,.T.);
#944=ORIENTED_EDGE('',*,*,#32,.F.);
#945=ORIENTED_EDGE('',*,*,#750,.F.);
#946=DIRECTION('',(0.,0.,-1.));
#947=VECTOR('',#946,1.);
#948=CARTESIAN_POINT('',(28.1781250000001,-7.14374999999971,12.7));
#949=LINE('',#948,#947);
#950=EDGE_CURVE('E347',#742,#797,#949,.T.);
#951=ORIENTED_EDGE('',*,*,#950,.T.);
#952=EDGE_LOOP('',(#943,#944,#945,#951));
#953=FACE_BOUND('',#952,.T.);
#954=ADVANCED_FACE('F497',(#953),#942,.T.);
#955=CARTESIAN_POINT('',(1.90500000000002,-1.90499999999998,12.7));
#956=DIRECTION('',(0.,0.,-1.));
#957=DIRECTION('',(-1.,0.,0.));
#958=AXIS2_PLACEMENT_3D('',#955,#956,#957);
#959=CYLINDRICAL_SURFACE('',#958,1.905);
#960=ORIENTED_EDGE('',*,*,#931,.T.);
#961=DIRECTION('',(0.,0.,-1.));
#962=VECTOR('',#961,1.);
#963=CARTESIAN_POINT('',(0.,-1.905,12.7));
#964=LINE('',#963,#962);
#965=EDGE_CURVE('E393',#616,#923,#964,.T.);
#966=ORIENTED_EDGE('',*,*,#965,.F.);
#967=ORIENTED_EDGE('',*,*,#617,.F.);
#968=ORIENTED_EDGE('',*,*,#152,.T.);
#969=EDGE_LOOP('',(#960,#966,#967,#968));
#970=FACE_BOUND('',#969,.T.);
#971=ADVANCED_FACE('F438',(#970),#959,.T.);
#972=CARTESIAN_POINT('',(0.,-1.905,12.7));
#973=DIRECTION('',(1.,0.,0.));
#974=DIRECTION('',(0.,1.,0.));
#975=AXIS2_PLACEMENT_3D('',#972,#973,#974);
#976=PLANE('',#975);
#977=ORIENTED_EDGE('',*,*,#924,.T.);
#978=DIRECTION('',(0.,0.,-1.));
#979=VECTOR('',#978,1.);
#980=CARTESIAN_POINT('',(3.1260978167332E-13,-29.845,12.7));
#981=LINE('',#980,#979);
#982=EDGE_CURVE('E390',#624,#915,#981,.T.);
#983=ORIENTED_EDGE('',*,*,#982,.F.);
#984=ORIENTED_EDGE('',*,*,#625,.F.);
#985=ORIENTED_EDGE('',*,*,#965,.T.);
#986=EDGE_LOOP('',(#977,#983,#984,#985));
#987=FACE_BOUND('',#986,.T.);
#988=ADVANCED_FACE('F622',(#987),#976,.F.);
#989=CARTESIAN_POINT('',(1.90500000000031,-29.845,12.7));
#990=DIRECTION('',(0.,0.,-1.));
#991=DIRECTION('',(-1.,0.,0.));
#992=AXIS2_PLACEMENT_3D('',#989,#990,#991);
#993=CYLINDRICAL_SURFACE('',#992,1.905);
#994=ORIENTED_EDGE('',*,*,#916,.T.);
#995=DIRECTION('',(0.,0.,-1.));
#996=VECTOR('',#995,1.);
#997=CARTESIAN_POINT('',(1.90500000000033,-31.75,12.7));
#998=LINE('',#997,#996);
#999=EDGE_CURVE('E387',#633,#906,#998,.T.);
#1000=ORIENTED_EDGE('',*,*,#999,.F.);
#1001=ORIENTED_EDGE('',*,*,#634,.F.);
#1002=ORIENTED_EDGE('',*,*,#982,.T.);
#1003=EDGE_LOOP('',(#994,#1000,#1001,#1002));
#1004=FACE_BOUND('',#1003,.T.);
#1005=ADVANCED_FACE('F619',(#1004),#993,.T.);
#1006=CARTESIAN_POINT('',(1.90500000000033,-31.75,12.7));
#1007=DIRECTION('',(0.,1.,0.));
#1008=DIRECTION('',(-1.,0.,0.));
#1009=AXIS2_PLACEMENT_3D('',#1006,#1007,#1008);
#1010=PLANE('',#1009);
#1011=ORIENTED_EDGE('',*,*,#907,.T.);
#1012=DIRECTION('',(0.,0.,-1.));
#1013=VECTOR('',#1012,1.);
#1014=CARTESIAN_POINT('',(28.1781250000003,-31.7499999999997,12.7));
#1015=LINE('',#1014,#1013);
#1016=EDGE_CURVE('E384',#641,#898,#1015,.T.);
#1017=ORIENTED_EDGE('',*,*,#1016,.F.);
#1018=ORIENTED_EDGE('',*,*,#642,.F.);
#1019=ORIENTED_EDGE('',*,*,#999,.T.);
#1020=EDGE_LOOP('',(#1011,#1017,#1018,#1019));
#1021=FACE_BOUND('',#1020,.T.);
#1022=ADVANCED_FACE('F614',(#1021),#1010,.F.);
#1023=CARTESIAN_POINT('',(28.1781250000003,-28.1781249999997,12.7));
#1024=DIRECTION('',(0.,0.,-1.));
#1025=DIRECTION('',(-1.,0.,0.));
#1026=AXIS2_PLACEMENT_3D('',#1023,#1024,#1025);
#1027=CYLINDRICAL_SURFACE('',#1026,3.571875);
#1028=ORIENTED_EDGE('',*,*,#899,.T.);
#1029=DIRECTION('',(0.,0.,-1.));
#1030=VECTOR('',#1029,1.);
#1031=CARTESIAN_POINT('',(28.1781250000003,-24.6062499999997,12.7));
#1032=LINE('',#1031,#1030);
#1033=EDGE_CURVE('E381',#650,#889,#1032,.T.);
#1034=ORIENTED_EDGE('',*,*,#1033,.F.);
#1035=ORIENTED_EDGE('',*,*,#651,.F.);
#1036=ORIENTED_EDGE('',*,*,#1016,.T.);
#1037=EDGE_LOOP('',(#1028,#1034,#1035,#1036));
#1038=FACE_BOUND('',#1037,.T.);
#1039=ADVANCED_FACE('F610',(#1038),#1027,.T.);
#1040=CARTESIAN_POINT('',(28.1781250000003,-24.6062499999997,12.7));
#1041=DIRECTION('',(0.,-1.,0.));
#1042=DIRECTION('',(1.,0.,0.));
#1043=AXIS2_PLACEMENT_3D('',#1040,#1041,#1042);
#1044=PLANE('',#1043);
#1045=ORIENTED_EDGE('',*,*,#890,.T.);
#1046=DIRECTION('',(0.,0.,-1.));
#1047=VECTOR('',#1046,1.);
#1048=CARTESIAN_POINT('',(27.9400000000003,-24.6062499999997,12.7));
#1049=LINE('',#1048,#1047);
#1050=EDGE_CURVE('E378',#658,#881,#1049,.T.);
#1051=ORIENTED_EDGE('',*,*,#1050,.F.);
#1052=ORIENTED_EDGE('',*,*,#659,.F.);
#1053=ORIENTED_EDGE('',*,*,#1033,.T.);
#1054=EDGE_LOOP('',(#1045,#1051,#1052,#1053));
#1055=FACE_BOUND('',#1054,.T.);
#1056=ADVANCED_FACE('F606',(#1055),#1044,.F.);
#1057=CARTESIAN_POINT('',(27.9400000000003,-25.5587499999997,12.7));
#1058=DIRECTION('',(0.,0.,-1.));
#1059=DIRECTION('',(-1.,0.,0.));
#1060=AXIS2_PLACEMENT_3D('',#1057,#1058,#1059);
#1061=CYLINDRICAL_SURFACE('',#1060,0.952500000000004);
#1062=ORIENTED_EDGE('',*,*,#882,.T.);
#1063=DIRECTION('',(0.,0.,-1.));
#1064=VECTOR('',#1063,1.);
#1065=CARTESIAN_POINT('',(27.9400000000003,-26.5112499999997,12.7));
#1066=LINE('',#1065,#1064);
#1067=EDGE_CURVE('E375',#667,#872,#1066,.T.);
#1068=ORIENTED_EDGE('',*,*,#1067,.F.);
#1069=ORIENTED_EDGE('',*,*,#668,.F.);
#1070=ORIENTED_EDGE('',*,*,#1050,.T.);
#1071=EDGE_LOOP('',(#1062,#1068,#1069,#1070));
#1072=FACE_BOUND('',#1071,.T.);
#1073=ADVANCED_FACE('F601',(#1072),#1061,.T.);
#1074=CARTESIAN_POINT('',(28.1781250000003,-26.5112499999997,12.7));
#1075=DIRECTION('',(0.,1.,0.));
#1076=DIRECTION('',(-1.,0.,0.));
#1077=AXIS2_PLACEMENT_3D('',#1074,#1075,#1076);
#1078=PLANE('',#1077);
#1079=ORIENTED_EDGE('',*,*,#873,.T.);
#1080=DIRECTION('',(0.,0.,-1.));
#1081=VECTOR('',#1080,1.);
#1082=CARTESIAN_POINT('',(28.1781250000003,-26.5112499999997,12.7));
#1083=LINE('',#1082,#1081);
#1084=EDGE_CURVE('E372',#675,#864,#1083,.T.);
#1085=ORIENTED_EDGE('',*,*,#1084,.F.);
#1086=ORIENTED_EDGE('',*,*,#676,.F.);
#1087=ORIENTED_EDGE('',*,*,#1067,.T.);
#1088=EDGE_LOOP('',(#1079,#1085,#1086,#1087));
#1089=FACE_BOUND('',#1088,.T.);
#1090=ADVANCED_FACE('F595',(#1089),#1078,.F.);
#1091=CARTESIAN_POINT('',(28.1781250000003,-28.1781249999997,12.7));
#1092=DIRECTION('',(0.,0.,-1.));
#1093=DIRECTION('',(-1.,0.,0.));
#1094=AXIS2_PLACEMENT_3D('',#1091,#1092,#1093);
#1095=CYLINDRICAL_SURFACE('',#1094,1.66687500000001);
#1096=ORIENTED_EDGE('',*,*,#865,.T.);
#1097=DIRECTION('',(0.,0.,-1.));
#1098=VECTOR('',#1097,1.);
#1099=CARTESIAN_POINT('',(28.1781250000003,-29.8449999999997,12.7));
#1100=LINE('',#1099,#1098);
#1101=EDGE_CURVE('E369',#684,#855,#1100,.T.);
#1102=ORIENTED_EDGE('',*,*,#1101,.F.);
#1103=ORIENTED_EDGE('',*,*,#685,.F.);
#1104=ORIENTED_EDGE('',*,*,#1084,.T.);
#1105=EDGE_LOOP('',(#1096,#1102,#1103,#1104));
#1106=FACE_BOUND('',#1105,.T.);
#1107=ADVANCED_FACE('F591',(#1106),#1095,.F.);
#1108=CARTESIAN_POINT('',(1.90500000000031,-29.845,12.7));
#1109=DIRECTION('',(0.,-1.,0.));
#1110=DIRECTION('',(1.,0.,0.));
#1111=AXIS2_PLACEMENT_3D('',#1108,#1109,#1110);
#1112=PLANE('',#1111);
#1113=ORIENTED_EDGE('',*,*,#856,.T.);
#1114=DIRECTION('',(0.,0.,-1.));
#1115=VECTOR('',#1114,1.);
#1116=CARTESIAN_POINT('',(1.90500000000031,-29.845,12.7));
#1117=LINE('',#1116,#1115);
#1118=EDGE_CURVE('E366',#692,#847,#1117,.T.);
#1119=ORIENTED_EDGE('',*,*,#1118,.F.);
#1120=ORIENTED_EDGE('',*,*,#693,.F.);
#1121=ORIENTED_EDGE('',*,*,#1101,.T.);
#1122=EDGE_LOOP('',(#1113,#1119,#1120,#1121));
#1123=FACE_BOUND('',#1122,.T.);
#1124=ADVANCED_FACE('F586',(#1123),#1112,.F.);
#1125=CARTESIAN_POINT('',(1.90500000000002,-1.90499999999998,12.7));
#1126=DIRECTION('',(-1.,0.,0.));
#1127=DIRECTION('',(0.,-1.,0.));
#1128=AXIS2_PLACEMENT_3D('',#1125,#1126,#1127);
#1129=PLANE('',#1128);
#1130=ORIENTED_EDGE('',*,*,#848,.T.);
#1131=DIRECTION('',(0.,0.,-1.));
#1132=VECTOR('',#1131,1.);
#1133=CARTESIAN_POINT('',(1.90500000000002,-1.90499999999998,12.7));
#1134=LINE('',#1133,#1132);
#1135=EDGE_CURVE('E363',#700,#839,#1134,.T.);
#1136=ORIENTED_EDGE('',*,*,#1135,.F.);
#1137=ORIENTED_EDGE('',*,*,#701,.F.);
#1138=ORIENTED_EDGE('',*,*,#1118,.T.);
#1139=EDGE_LOOP('',(#1130,#1136,#1137,#1138));
#1140=FACE_BOUND('',#1139,.T.);
#1141=ADVANCED_FACE('F580',(#1140),#1129,.F.);
#1142=CARTESIAN_POINT('',(28.178125,-1.90499999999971,12.7));
#1143=DIRECTION('',(0.,1.,0.));
#1144=DIRECTION('',(-1.,0.,0.));
#1145=AXIS2_PLACEMENT_3D('',#1142,#1143,#1144);
#1146=PLANE('',#1145);
#1147=ORIENTED_EDGE('',*,*,#840,.T.);
#1148=DIRECTION('',(0.,0.,-1.));
#1149=VECTOR('',#1148,1.);
#1150=CARTESIAN_POINT('',(28.178125,-1.90499999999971,12.7));
#1151=LINE('',#1150,#1149);
#1152=EDGE_CURVE('E360',#708,#831,#1151,.T.);
#1153=ORIENTED_EDGE('',*,*,#1152,.F.);
#1154=ORIENTED_EDGE('',*,*,#709,.F.);
#1155=ORIENTED_EDGE('',*,*,#1135,.T.);
#1156=EDGE_LOOP('',(#1147,#1153,#1154,#1155));
#1157=FACE_BOUND('',#1156,.T.);
#1158=ADVANCED_FACE('F576',(#1157),#1146,.F.);
#1159=CARTESIAN_POINT('',(28.178125,-3.57187499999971,12.7));
#1160=DIRECTION('',(0.,0.,-1.));
#1161=DIRECTION('',(-1.,0.,0.));
#1162=AXIS2_PLACEMENT_3D('',#1159,#1160,#1161);
#1163=CYLINDRICAL_SURFACE('',#1162,1.666875);
#1164=ORIENTED_EDGE('',*,*,#832,.T.);
#1165=DIRECTION('',(0.,0.,-1.));
#1166=VECTOR('',#1165,1.);
#1167=CARTESIAN_POINT('',(28.1781250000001,-5.23874999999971,12.7));
#1168=LINE('',#1167,#1166);
#1169=EDGE_CURVE('E357',#717,#822,#1168,.T.);
#1170=ORIENTED_EDGE('',*,*,#1169,.F.);
#1171=ORIENTED_EDGE('',*,*,#718,.F.);
#1172=ORIENTED_EDGE('',*,*,#1152,.T.);
#1173=EDGE_LOOP('',(#1164,#1170,#1171,#1172));
#1174=FACE_BOUND('',#1173,.T.);
#1175=ADVANCED_FACE('F572',(#1174),#1163,.F.);
#1176=CARTESIAN_POINT('',(28.1781250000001,-5.23874999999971,12.7));
#1177=DIRECTION('',(0.,-1.,0.));
#1178=DIRECTION('',(1.,0.,0.));
#1179=AXIS2_PLACEMENT_3D('',#1176,#1177,#1178);
#1180=PLANE('',#1179);
#1181=ORIENTED_EDGE('',*,*,#823,.T.);
#1182=DIRECTION('',(0.,0.,-1.));
#1183=VECTOR('',#1182,1.);
#1184=CARTESIAN_POINT('',(27.9400000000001,-5.23874999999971,12.7));
#1185=LINE('',#1184,#1183);
#1186=EDGE_CURVE('E354',#725,#814,#1185,.T.);
#1187=ORIENTED_EDGE('',*,*,#1186,.F.);
#1188=ORIENTED_EDGE('',*,*,#726,.F.);
#1189=ORIENTED_EDGE('',*,*,#1169,.T.);
#1190=EDGE_LOOP('',(#1181,#1187,#1188,#1189));
#1191=FACE_BOUND('',#1190,.T.);
#1192=ADVANCED_FACE('F565',(#1191),#1180,.F.);
#1193=CARTESIAN_POINT('',(27.9400000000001,-6.19124999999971,12.7));
#1194=DIRECTION('',(0.,0.,-1.));
#1195=DIRECTION('',(-1.,0.,0.));
#1196=AXIS2_PLACEMENT_3D('',#1193,#1194,#1195);
#1197=CYLINDRICAL_SURFACE('',#1196,0.9525);
#1198=ORIENTED_EDGE('',*,*,#815,.T.);
#1199=DIRECTION('',(0.,0.,-1.));
#1200=VECTOR('',#1199,1.);
#1201=CARTESIAN_POINT('',(27.9400000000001,-7.14374999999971,12.7));
#1202=LINE('',#1201,#1200);
#1203=EDGE_CURVE('E350',#734,#805,#1202,.T.);
#1204=ORIENTED_EDGE('',*,*,#1203,.F.);
#1205=ORIENTED_EDGE('',*,*,#735,.F.);
#1206=ORIENTED_EDGE('',*,*,#1186,.T.);
#1207=EDGE_LOOP('',(#1198,#1204,#1205,#1206));
#1208=FACE_BOUND('',#1207,.T.);
#1209=ADVANCED_FACE('F567',(#1208),#1197,.T.);
#1210=CARTESIAN_POINT('',(28.1781250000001,-7.14374999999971,12.7));
#1211=DIRECTION('',(0.,1.,0.));
#1212=DIRECTION('',(-1.,0.,0.));
#1213=AXIS2_PLACEMENT_3D('',#1210,#1211,#1212);
#1214=PLANE('',#1213);
#1215=ORIENTED_EDGE('',*,*,#806,.T.);
#1216=ORIENTED_EDGE('',*,*,#950,.F.);
#1217=ORIENTED_EDGE('',*,*,#743,.F.);
#1218=ORIENTED_EDGE('',*,*,#1203,.T.);
#1219=EDGE_LOOP('',(#1215,#1216,#1217,#1218));
#1220=FACE_BOUND('',#1219,.T.);
#1221=ADVANCED_FACE('F493',(#1220),#1214,.F.);
#1222=CLOSED_SHELL('',(#58,#100,#131,#164,#197,#228,#261,#292,#325,#356,#389,#420,#451,#482,
#515,#546,#579,#601,#769,#937,#954,#971,#988,#1005,#1022,#1039,#1056,#1073,#1090,#1107,#1124,
#1141,#1158,#1175,#1192,#1209,#1221));
#1223=MANIFOLD_SOLID_BREP('B2',#1222);
#1224=ADVANCED_BREP_SHAPE_REPRESENTATION('',(#18,#1223),#14);
#1225=SHAPE_DEFINITION_REPRESENTATION(#9,#1224);
ENDSEC;
END-ISO-10303-21;
